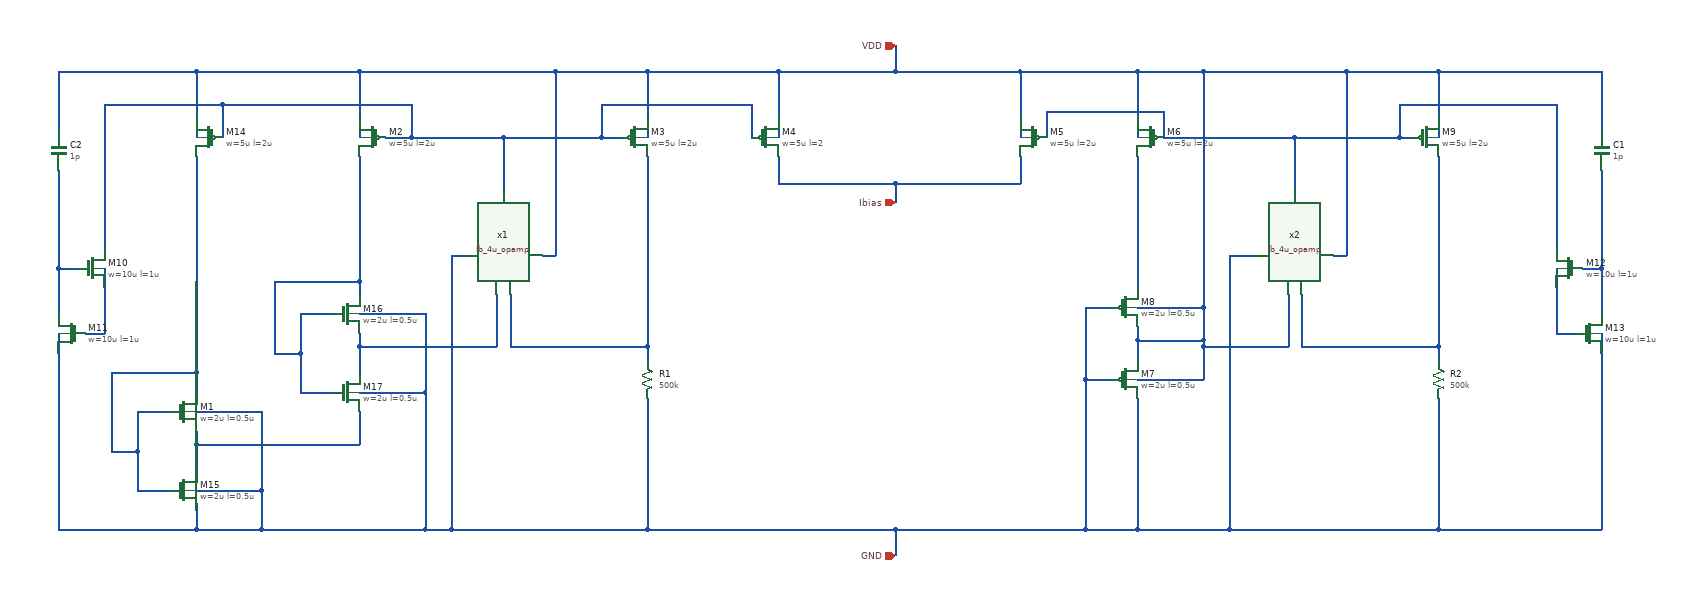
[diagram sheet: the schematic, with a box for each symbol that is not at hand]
v {xschem version=3.4.7 file_version=1.2}
G {}
K {}
V {}
S {}
E {}
N 1620 -790 1620 -750 {lab=Ibias}
N 1800 -750 1990 -750 {lab=Ibias}
N 1990 -790 1990 -750 {lab=Ibias}
N 1800 -750 1800 -720 {lab=Ibias}
N 1620 -750 1800 -750 {lab=Ibias}
N 2210 -860 2210 -820 {lab=#net1}
N 2090 -560 2130 -560 {lab=GND}
N 2090 -450 2130 -450 {lab=GND}
N 2570 -820 2590 -820 {lab=#net1}
N 2410 -820 2410 -740 {lab=#net1}
N 2210 -820 2410 -820 {lab=#net1}
N 2570 -870 2570 -820 {lab=#net1}
N 2410 -820 2570 -820 {lab=#net1}
N 2810 -870 2810 -650 {lab=#net1}
N 2570 -870 2810 -870 {lab=#net1}
N 1620 -920 1620 -820 {lab=VDD}
N 1990 -920 1990 -820 {lab=VDD}
N 2170 -920 2170 -820 {lab=VDD}
N 2630 -920 2630 -820 {lab=VDD}
N 2880 -620 2880 -550 {lab=#net2}
N 2630 -920 2880 -920 {lab=VDD}
N 2850 -620 2880 -620 {lab=#net2}
N 2810 -520 2840 -520 {lab=#net3}
N 2880 -520 2880 -220 {lab=GND}
N 2810 -620 2810 -520 {lab=#net3}
N 2880 -920 2880 -830 {lab=VDD}
N 2880 -770 2880 -620 {lab=#net2}
N 590 -870 590 -650 {lab=#net4}
N 520 -620 520 -550 {lab=#net5}
N 520 -620 550 -620 {lab=#net5}
N 560 -520 590 -520 {lab=#net6}
N 590 -620 590 -520 {lab=#net6}
N 520 -920 520 -830 {lab=VDD}
N 520 -770 520 -620 {lab=#net5}
N 730 -920 980 -920 {lab=VDD}
N 1420 -920 1420 -820 {lab=VDD}
N 1280 -920 1420 -920 {lab=VDD}
N 1350 -820 1380 -820 {lab=#net4}
N 1350 -870 1350 -820 {lab=#net4}
N 1580 -870 1580 -820 {lab=#net4}
N 2030 -860 2030 -820 {lab=#net1}
N 1200 -820 1350 -820 {lab=#net4}
N 980 -920 980 -820 {lab=VDD}
N 1200 -820 1200 -740 {lab=#net4}
N 1060 -820 1200 -820 {lab=#net4}
N 1260 -640 1280 -640 {lab=VDD}
N 1280 -920 1280 -640 {lab=VDD}
N 980 -920 1280 -920 {lab=VDD}
N 980 -500 980 -460 {lab=#net7}
N 980 -550 1080 -550 {lab=GND}
N 1080 -550 1080 -430 {lab=GND}
N 980 -430 1080 -430 {lab=GND}
N 890 -550 940 -550 {lab=#net8}
N 890 -490 890 -430 {lab=#net8}
N 890 -430 940 -430 {lab=#net8}
N 980 -600 980 -580 {lab=#net8}
N 850 -490 890 -490 {lab=#net8}
N 890 -550 890 -490 {lab=#net8}
N 850 -600 850 -490 {lab=#net8}
N 850 -600 980 -600 {lab=#net8}
N 980 -790 980 -600 {lab=#net8}
N 980 -500 1190 -500 {lab=#net7}
N 980 -520 980 -500 {lab=#net7}
N 1190 -580 1190 -500 {lab=#net7}
N 730 -350 730 -310 {lab=#net9}
N 730 -400 830 -400 {lab=GND}
N 830 -400 830 -280 {lab=GND}
N 730 -280 830 -280 {lab=GND}
N 640 -400 690 -400 {lab=#net10}
N 640 -340 640 -280 {lab=#net10}
N 640 -280 690 -280 {lab=#net10}
N 600 -340 640 -340 {lab=#net10}
N 640 -400 640 -340 {lab=#net10}
N 730 -350 980 -350 {lab=#net9}
N 730 -370 730 -350 {lab=#net9}
N 980 -400 980 -350 {lab=#net9}
N 730 -460 730 -430 {lab=#net10}
N 730 -920 730 -820 {lab=VDD}
N 520 -920 730 -920 {lab=VDD}
N 770 -870 770 -820 {lab=#net4}
N 770 -870 1060 -870 {lab=#net4}
N 1060 -870 1060 -820 {lab=#net4}
N 1020 -820 1060 -820 {lab=#net4}
N 590 -870 770 -870 {lab=#net4}
N 520 -520 520 -220 {lab=GND}
N 520 -220 730 -220 {lab=GND}
N 730 -260 730 -220 {lab=GND}
N 600 -460 600 -340 {lab=#net10}
N 600 -460 730 -460 {lab=#net10}
N 730 -790 730 -460 {lab=#net10}
N 2630 -220 2880 -220 {lab=GND}
N 2090 -560 2090 -450 {lab=GND}
N 2310 -220 2630 -220 {lab=GND}
N 1080 -430 1080 -220 {lab=GND}
N 830 -220 1080 -220 {lab=GND}
N 830 -280 830 -220 {lab=GND}
N 730 -220 830 -220 {lab=GND}
N 2170 -560 2270 -560 {lab=VDD}
N 2170 -450 2270 -450 {lab=VDD}
N 2490 -920 2630 -920 {lab=VDD}
N 1420 -500 1420 -480 {lab=#net11}
N 1420 -420 1420 -220 {lab=GND}
N 1120 -220 1420 -220 {lab=GND}
N 1210 -580 1210 -500 {lab=#net11}
N 1210 -500 1420 -500 {lab=#net11}
N 1420 -790 1420 -500 {lab=#net11}
N 2630 -500 2630 -480 {lab=#net12}
N 2630 -420 2630 -220 {lab=GND}
N 2420 -500 2630 -500 {lab=#net12}
N 2630 -790 2630 -500 {lab=#net12}
N 2420 -580 2420 -500 {lab=#net12}
N 2270 -500 2270 -450 {lab=VDD}
N 2400 -580 2400 -500 {lab=VDD}
N 2170 -790 2170 -590 {lab=#net13}
N 2170 -420 2170 -220 {lab=GND}
N 2170 -510 2170 -480 {lab=VDD}
N 2270 -920 2270 -560 {lab=VDD}
N 2170 -920 2270 -920 {lab=VDD}
N 2310 -640 2350 -640 {lab=GND}
N 2310 -640 2310 -220 {lab=GND}
N 2170 -220 2310 -220 {lab=GND}
N 2470 -640 2490 -640 {lab=VDD}
N 2490 -920 2490 -640 {lab=VDD}
N 2270 -920 2490 -920 {lab=VDD}
N 2090 -220 2170 -220 {lab=GND}
N 2090 -450 2090 -220 {lab=GND}
N 1800 -220 2090 -220 {lab=GND}
N 2030 -860 2210 -860 {lab=#net1}
N 1350 -870 1580 -870 {lab=#net4}
N 1420 -920 1620 -920 {lab=VDD}
N 1990 -920 2170 -920 {lab=VDD}
N 1800 -920 1990 -920 {lab=VDD}
N 1800 -960 1800 -920 {lab=VDD}
N 1620 -920 1800 -920 {lab=VDD}
N 1800 -220 1800 -180 {lab=GND}
N 1420 -220 1800 -220 {lab=GND}
N 1120 -640 1140 -640 {lab=GND}
N 1120 -640 1120 -220 {lab=GND}
N 1080 -220 1120 -220 {lab=GND}
N 2170 -510 2270 -510 {lab=VDD}
N 2170 -530 2170 -510 {lab=VDD}
N 2270 -560 2270 -510 {lab=VDD}
N 2270 -500 2400 -500 {lab=VDD}
N 2270 -510 2270 -500 {lab=VDD}
C {sg13g2_pr/sg13_lv_pmos.sym} 1000 -820 0 1 {name=M2
l=2u
w=5u
ng=1
m=1
model=sg13_lv_pmos
spiceprefix=X
}
C {sg13g2_pr/sg13_lv_pmos.sym} 1400 -820 0 0 {name=M3
l=2u
w=5u
ng=1
m=1
model=sg13_lv_pmos
spiceprefix=X
}
C {sg13g2_pr/sg13_lv_pmos.sym} 1600 -820 0 0 {name=M4
l=2
w=5u
ng=1
m=1
model=sg13_lv_pmos
spiceprefix=X
}
C {sg13g2_pr/sg13_lv_pmos.sym} 2010 -820 0 1 {name=M5
l=2u
w=5u
ng=1
m=1
model=sg13_lv_pmos
spiceprefix=X
}
C {sg13g2_pr/sg13_lv_pmos.sym} 2190 -820 0 1 {name=M6
l=2u
w=5u
ng=1
m=1
model=sg13_lv_pmos
spiceprefix=X
}
C {sg13g2_pr/sg13_lv_pmos.sym} 2150 -450 0 0 {name=M7
l=0.5u
w=2u
ng=1
m=30
model=sg13_lv_pmos
spiceprefix=X
}
C {sg13g2_pr/sg13_lv_pmos.sym} 2150 -560 0 0 {name=M8
l=0.5u
w=2u
ng=1
m=1
model=sg13_lv_pmos
spiceprefix=X
}
C {sg13g2_pr/sg13_lv_pmos.sym} 2610 -820 0 0 {name=M9
l=2u
w=5u
ng=1
m=1
model=sg13_lv_pmos
spiceprefix=X
}
C {sg13g2_pr/sg13_lv_nmos.sym} 2830 -620 0 1 {name=M12
l=1u
w=10u
ng=1
m=1
model=sg13_lv_nmos
spiceprefix=X
}
C {sg13g2_pr/sg13_lv_nmos.sym} 2860 -520 0 0 {name=M13
l=1u
w=10u
ng=1
m=1
model=sg13_lv_nmos
spiceprefix=X
}
C {sg13g2_pr/sg13_lv_nmos.sym} 960 -550 0 0 {name=M16
l=0.5u
w=2u
ng=1
m=30
model=sg13_lv_nmos
spiceprefix=X
}
C {sg13g2_pr/sg13_lv_nmos.sym} 960 -430 0 0 {name=M17
l=0.5u
w=2u
ng=1
m=1
model=sg13_lv_nmos
spiceprefix=X
}
C {capa.sym} 2880 -800 0 0 {name=C1
m=1
value=1p
footprint=1206
device="ceramic capacitor"}
C {sg13g2_pr/sg13_lv_nmos.sym} 570 -620 0 0 {name=M10
l=1u
w=10u
ng=1
m=1
model=sg13_lv_nmos
spiceprefix=X
}
C {sg13g2_pr/sg13_lv_nmos.sym} 540 -520 0 1 {name=M11
l=1u
w=10u
ng=1
m=1
model=sg13_lv_nmos
spiceprefix=X
}
C {capa.sym} 520 -800 0 1 {name=C2
m=1
value=1p
footprint=1206
device="ceramic capacitor"}
C {sg13g2_pr/sg13_lv_pmos.sym} 750 -820 0 1 {name=M14
l=2u
w=5u
ng=1
m=1
model=sg13_lv_pmos
spiceprefix=X
}
C {sg13g2_pr/sg13_lv_nmos.sym} 710 -400 0 0 {name=M1
l=0.5u
w=2u
ng=1
m=30
model=sg13_lv_nmos
spiceprefix=X
}
C {sg13g2_pr/sg13_lv_nmos.sym} 710 -280 0 0 {name=M15
l=0.5u
w=2u
ng=1
m=1
model=sg13_lv_nmos
spiceprefix=X
}
C {res.sym} 1420 -450 0 0 {name=R1
value=500k
footprint=1206
device=resistor
m=1}
C {res.sym} 2630 -450 0 0 {name=R2
value=500k
footprint=1206
device=resistor
m=1}
C {iopin.sym} 1800 -960 0 0 {name=p1 lab=VDD}
C {iopin.sym} 1800 -180 0 0 {name=p2 lab=GND}
C {iopin.sym} 1800 -720 0 0 {name=p3 lab=Ibias}
C {SSDOR_1V_v1/components/Ib_4u/Ib_4u_opamp/Ib_4u_opamp.sym} 1140 -580 1 1 {name=x1}
C {SSDOR_1V_v1/components/Ib_4u/Ib_4u_opamp/Ib_4u_opamp.sym} 2350 -580 1 1 {name=x2}
